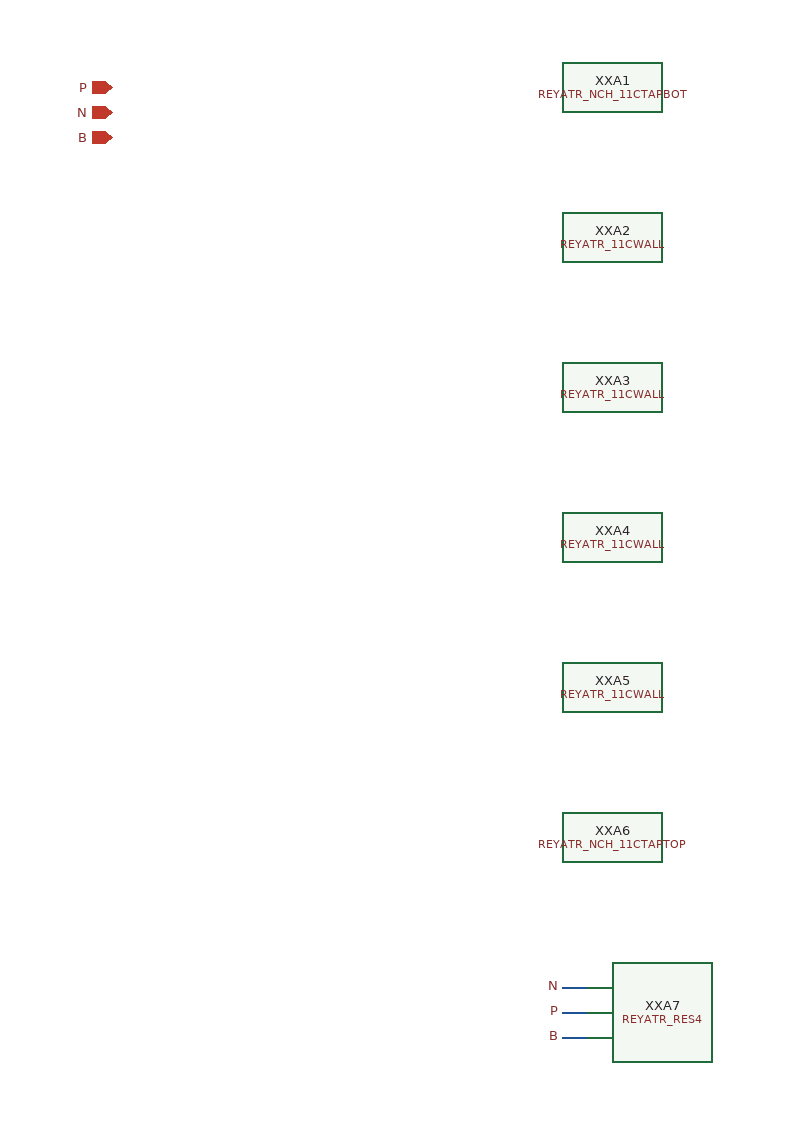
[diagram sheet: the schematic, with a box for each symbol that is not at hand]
v {xschem version=3.0.0 file_version=1.2 }
G {}
K {}
V {}
S {}
E {}
C {devices/iopin.sym} 0 0 0 0 {name=p0 lab=P}
C {devices/iopin.sym} 0 20 0 0 {name=p1 lab=N}
C {devices/iopin.sym} 0 40 0 0 {name=p2 lab=B}
C {LELO_TEMP_SKY130A/REYATR_NCH_11CTAPBOT.sym} 400 0 0 0 {name=XXA1}
C {LELO_TEMP_SKY130A/REYATR_11CWALL.sym} 400 120.0 0 0 {name=XXA2}
C {LELO_TEMP_SKY130A/REYATR_11CWALL.sym} 400 240.0 0 0 {name=XXA3}
C {LELO_TEMP_SKY130A/REYATR_11CWALL.sym} 400 360.0 0 0 {name=XXA4}
C {LELO_TEMP_SKY130A/REYATR_11CWALL.sym} 400 480.0 0 0 {name=XXA5}
C {LELO_TEMP_SKY130A/REYATR_NCH_11CTAPTOP.sym} 400 600.0 0 0 {name=XXA6}
C {LELO_TEMP_SKY130A/REYATR_RES4.sym} 400 720.0 0 0 {name=XXA7}
N 360.0 720.0 380.0 720.0 {lab=N}
C {devices/lab_pin.sym} 360.0 720.0 0 0 {name=l0 sig_type=std_logic lab=N }
N 360.0 740.0 380.0 740.0 {lab=P}
C {devices/lab_pin.sym} 360.0 740.0 0 0 {name=l1 sig_type=std_logic lab=P }
N 360.0 760.0 380.0 760.0 {lab=B}
C {devices/lab_pin.sym} 360.0 760.0 0 0 {name=l2 sig_type=std_logic lab=B }
